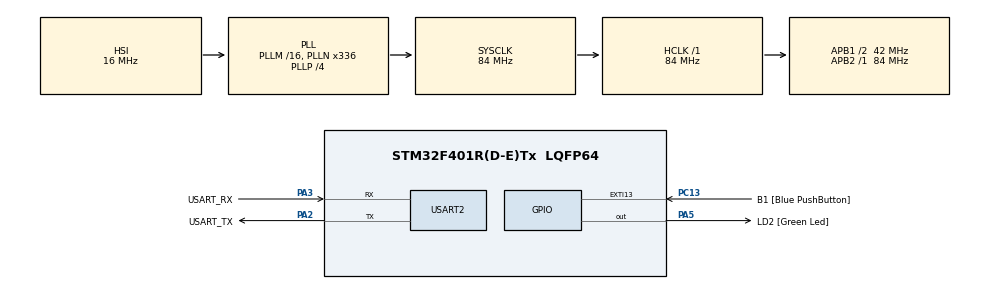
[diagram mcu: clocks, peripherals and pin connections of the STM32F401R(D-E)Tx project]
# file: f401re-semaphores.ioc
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FREERTOS.Tasks01=defaultTask,24,128,task_main,As weak,NULL,Dynamic,NULL,NULL
FREERTOS.configUSE_NEWLIB_REENTRANT=1
Mcu.Family=STM32F4
Mcu.Name=STM32F401R(D-E)Tx
Mcu.Package=LQFP64
NVIC.PriorityGroup=NVIC_PRIORITYGROUP_4
NVIC.TIM1_UP_TIM10_IRQn=true\:15\:0\:false\:false\:true\:false\:false\:true\:true
NVIC.TimeBase=TIM1_UP_TIM10_IRQn
NVIC.TimeBaseIP=TIM10
PA13.GPIO_Label=TMS
PA13.Mode=Trace_Asynchronous_SW
PA13.Signal=SYS_JTMS-SWDIO
PA14.GPIO_Label=TCK
PA14.Mode=Trace_Asynchronous_SW
PA14.Signal=SYS_JTCK-SWCLK
PA2.GPIO_Label=USART_TX
PA2.GPIO_Mode=GPIO_MODE_AF_PP
PA2.GPIO_PuPd=GPIO_NOPULL
PA2.GPIO_Speed=GPIO_SPEED_FREQ_LOW
PA2.Mode=Asynchronous
PA2.Signal=USART2_TX
PA3.GPIO_Label=USART_RX
PA3.GPIO_Mode=GPIO_MODE_AF_PP
PA3.GPIO_PuPd=GPIO_NOPULL
PA3.GPIO_Speed=GPIO_SPEED_FREQ_LOW
PA3.Mode=Asynchronous
PA3.Signal=USART2_RX
PA5.GPIO_Label=LD2 [Green Led]
PA5.GPIO_Mode=GPIO_MODE_OUTPUT_PP
PA5.GPIO_PuPd=GPIO_NOPULL
PA5.GPIO_Speed=GPIO_SPEED_FREQ_LOW
PA5.Signal=GPIO_Output
PB3.GPIO_Label=SWO
PB3.Mode=Trace_Asynchronous_SW
PB3.Signal=SYS_JTDO-SWO
PC13-ANTI_TAMP.GPIO_Label=B1 [Blue PushButton]
PC13-ANTI_TAMP.GPIO_ModeDefaultEXTI=GPIO_MODE_IT_FALLING
PC13-ANTI_TAMP.GPIO_PuPd=GPIO_NOPULL
PC13-ANTI_TAMP.Signal=GPXTI13
PC14-OSC32_IN.Mode=LSE-External-Oscillator
PC14-OSC32_IN.Signal=RCC_OSC32_IN
PC15-OSC32_OUT.Mode=LSE-External-Oscillator
PC15-OSC32_OUT.Signal=RCC_OSC32_OUT
PH0\ -\ OSC_IN.Mode=HSE-External-Clock-Source
PH0\ -\ OSC_IN.Signal=RCC_OSC_IN
PH1\ -\ OSC_OUT.Mode=HSE-External-Clock-Source
PH1\ -\ OSC_OUT.Signal=RCC_OSC_OUT
ProjectManager.HeapSize=0x200
ProjectManager.StackSize=0x400
ProjectManager.TargetToolchain=STM32CubeIDE
RCC.48MHZClocksFreq_Value=48000000
RCC.AHBFreq_Value=84000000
RCC.APB1CLKDivider=RCC_HCLK_DIV2
RCC.APB1Freq_Value=42000000
RCC.APB1TimFreq_Value=84000000
RCC.APB2Freq_Value=84000000
RCC.APB2TimFreq_Value=84000000
RCC.CortexFreq_Value=84000000
RCC.HCLKFreq_Value=84000000
RCC.HSE_VALUE=8000000
RCC.HSI_VALUE=16000000
RCC.PLLN=336
RCC.PLLP=RCC_PLLP_DIV4
RCC.PLLQ=7
RCC.SYSCLKFreq_VALUE=84000000
RCC.SYSCLKSource=RCC_SYSCLKSOURCE_PLLCLK
RCC.VCOOutputFreq_Value=336000000
USART2.VirtualMode=VM_ASYNC
VP_FREERTOS_VS_CMSIS_V2.Mode=CMSIS_V2
VP_SYS_VS_tim10.Mode=TIM10
board=NUCLEO-F401RE

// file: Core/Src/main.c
/* USER CODE BEGIN Header */
/**
  ******************************************************************************
  * @file           : main.c
  * @brief          : Main program body
  ******************************************************************************
  * @attention
  *
  * Copyright (c) 2025 STMicroelectronics.
  * All rights reserved.
  *
  * This software is licensed under terms that can be found in the LICENSE file
  * in the root directory of this software component.
  * If no LICENSE file comes with this software, it is provided AS-IS.
  *
  ******************************************************************************
  */
/* USER CODE END Header */
#include "main.h"
#include "cmsis_os.h"

/* USER CODE BEGIN Includes */
#include "stdio.h"
#include "string.h"
#include "freertos_defines.h"
/* USER CODE END Includes */

UART_HandleTypeDef huart2;

/* Definitions for defaultTask */
osThreadId_t defaultTaskHandle;
const osThreadAttr_t defaultTask_attributes = {
  .name = "defaultTask",
  .stack_size = 128 * 4,
  .priority = (osPriority_t) osPriorityNormal,
};
/* USER CODE BEGIN PV */

TaskHandle_t handle_task_main;
TaskHandle_t handle_task_green;
TaskHandle_t handle_task_blue;
TaskHandle_t handle_task_red;

SemaphoreHandle_t handle_semap_sem1;
SemaphoreHandle_t handle_semap_sem2;

/* USER CODE END PV */

void SystemClock_Config(void);
static void MX_GPIO_Init(void);
static void MX_USART2_UART_Init(void);
void task_main(void *argument);

int main(void)
{

  /* USER CODE BEGIN 1 */
  BaseType_t status;
  /* USER CODE END 1 */

  /* MCU Configuration--------------------------------------------------------*/

  /* Reset of all peripherals, Initializes the Flash interface and the Systick. */
  HAL_Init();

  /* Configure the system clock */
  SystemClock_Config();

  /* Initialize all configured peripherals */
  MX_GPIO_Init();
  MX_USART2_UART_Init();

  /* Init scheduler */
  osKernelInitialize();

  /* USER CODE BEGIN RTOS_SEMAPHORES */
  /* add semaphores, ... */
  handle_semap_sem1 = NULL;
  handle_semap_sem1 = xSemaphoreCreateBinary();
  xSemaphoreGive(handle_semap_sem1);
  //assert_param(handle_semap_sem1 != NULL);
  handle_semap_sem2 = NULL;
  handle_semap_sem2 = xSemaphoreCreateBinary();

  /* USER CODE END RTOS_SEMAPHORES */

  /* Create the thread(s) */
  /* creation of defaultTask */
  //defaultTaskHandle = osThreadNew(task_main, NULL, &defaultTask_attributes);

  /* USER CODE BEGIN RTOS_THREADS */
  /* add threads, ... */

  status = xTaskCreate(task_main, "Main task", 64, NULL, osPriorityNormal, &handle_task_main);
  //assert_param(status == pdPASS);

#ifdef HIGH_PRIORITY_EXAMPLE
  status = xTaskCreate(task_green, "Blinking green led task", 128, NULL, osPriorityHigh, &handle_task_green);

  //assert_param(status == pdPASS);
#else
  status = xTaskCreate(task_green, "Blinking green led task", 128, NULL, osPriorityNormal, &handle_task_green);
#endif

#ifdef HIGH_PRIORITY_EXAMPLE
  status = xTaskCreate(task_blue, "Blinking blue led task", 128, NULL, osPriorityNormal4, &handle_task_blue);
#else
  status = xTaskCreate(task_blue, "Blinking blue led task", 128, NULL, osPriorityNormal, &handle_task_blue);
#endif

#ifdef HIGH_PRIORITY_EXAMPLE
  status = xTaskCreate(task_red, "Blinking red led task", 64, NULL, osPriorityNormal, &handle_task_red);
#else
  status = xTaskCreate(task_red, "Blinking red led task", 64, NULL, osPriorityNormal, &handle_task_red);
#endif

  //assert_param(status == pdPASS);
  /* USER CODE END RTOS_THREADS */

  /* Start scheduler */
  osKernelStart();

  /* We should never get here as control is now taken by the scheduler */

  /* Infinite loop */
  while (1)
  {

  }
}

void SystemClock_Config(void)
{
  RCC_OscInitTypeDef RCC_OscInitStruct = {0};
  RCC_ClkInitTypeDef RCC_ClkInitStruct = {0};

  /** Configure the main internal regulator output voltage
  */
  __HAL_RCC_PWR_CLK_ENABLE();
  __HAL_PWR_VOLTAGESCALING_CONFIG(PWR_REGULATOR_VOLTAGE_SCALE2);

  /** Initializes the RCC Oscillators according to the specified parameters
  * in the RCC_OscInitTypeDef structure.
  */
  RCC_OscInitStruct.OscillatorType = RCC_OSCILLATORTYPE_HSI;
  RCC_OscInitStruct.HSIState = RCC_HSI_ON;
  RCC_OscInitStruct.HSICalibrationValue = RCC_HSICALIBRATION_DEFAULT;
  RCC_OscInitStruct.PLL.PLLState = RCC_PLL_ON;
  RCC_OscInitStruct.PLL.PLLSource = RCC_PLLSOURCE_HSI;
  RCC_OscInitStruct.PLL.PLLM = 16;
  RCC_OscInitStruct.PLL.PLLN = 336;
  RCC_OscInitStruct.PLL.PLLP = RCC_PLLP_DIV4;
  RCC_OscInitStruct.PLL.PLLQ = 7;
  if (HAL_RCC_OscConfig(&RCC_OscInitStruct) != HAL_OK)
  {
    Error_Handler();
  }

  /** Initializes the CPU, AHB and APB buses clocks
  */
  RCC_ClkInitStruct.ClockType = RCC_CLOCKTYPE_HCLK|RCC_CLOCKTYPE_SYSCLK
                              |RCC_CLOCKTYPE_PCLK1|RCC_CLOCKTYPE_PCLK2;
  RCC_ClkInitStruct.SYSCLKSource = RCC_SYSCLKSOURCE_PLLCLK;
  RCC_ClkInitStruct.AHBCLKDivider = RCC_SYSCLK_DIV1;
  RCC_ClkInitStruct.APB1CLKDivider = RCC_HCLK_DIV2;
  RCC_ClkInitStruct.APB2CLKDivider = RCC_HCLK_DIV1;

  if (HAL_RCC_ClockConfig(&RCC_ClkInitStruct, FLASH_LATENCY_2) != HAL_OK)
  {
    Error_Handler();
  }
}

static void MX_USART2_UART_Init(void)
{

  huart2.Instance = USART2;
  huart2.Init.BaudRate = 115200;
  huart2.Init.WordLength = UART_WORDLENGTH_8B;
  huart2.Init.StopBits = UART_STOPBITS_1;
  huart2.Init.Parity = UART_PARITY_NONE;
  huart2.Init.Mode = UART_MODE_TX_RX;
  huart2.Init.HwFlowCtl = UART_HWCONTROL_NONE;
  huart2.Init.OverSampling = UART_OVERSAMPLING_16;
  if (HAL_UART_Init(&huart2) != HAL_OK)
  {
    Error_Handler();
  }

}

static void MX_GPIO_Init(void)
{
  GPIO_InitTypeDef GPIO_InitStruct = {0};

  /* GPIO Ports Clock Enable */
  __HAL_RCC_GPIOC_CLK_ENABLE();
  __HAL_RCC_GPIOH_CLK_ENABLE();
  __HAL_RCC_GPIOA_CLK_ENABLE();
  __HAL_RCC_GPIOB_CLK_ENABLE();

  /*Configure GPIO pin Output Level */
  HAL_GPIO_WritePin(GPIOA, LED_GREEN_Pin|LED_BLUE_Pin|LED_RED_Pin, GPIO_PIN_RESET);

  /*Configure GPIO pin : B1_Pin */
  GPIO_InitStruct.Pin = B1_Pin;
  GPIO_InitStruct.Mode = GPIO_MODE_IT_FALLING;
  GPIO_InitStruct.Pull = GPIO_NOPULL;
  HAL_GPIO_Init(B1_GPIO_Port, &GPIO_InitStruct);

  /*Configure GPIO pins : LED_GREEN_Pin LED_BLUE_Pin LED_RED_Pin */
  GPIO_InitStruct.Pin = LED_GREEN_Pin|LED_BLUE_Pin|LED_RED_Pin;
  GPIO_InitStruct.Mode = GPIO_MODE_OUTPUT_PP;
  GPIO_InitStruct.Pull = GPIO_NOPULL;
  GPIO_InitStruct.Speed = GPIO_SPEED_FREQ_LOW;
  HAL_GPIO_Init(GPIOA, &GPIO_InitStruct);

}

__weak void task_main(void *argument)
{
}

void HAL_TIM_PeriodElapsedCallback(TIM_HandleTypeDef *htim)
{
  if (htim->Instance == TIM10) {
    HAL_IncTick();
  }
}

void Error_Handler(void)
{
  __disable_irq();
  while (1)
  {
  }
}

#ifdef  USE_FULL_ASSERT
/**
  * @brief  Reports the name of the source file and the source line number
  *         where the assert_param error has occurred.
  * @param  file: pointer to the source file name
  * @param  line: assert_param error line source number
  * @retval None
  */
void assert_failed(uint8_t *file, uint32_t line)
{
  /* USER CODE BEGIN 6 */
  /* User can add his own implementation to report the file name and line number,
     ex: printf("Wrong parameters value: file %s on line %d\r\n", file, line) */

	// Guardar error en una variable global o log (opcional)
	static uint32_t last_assert_line = 0;
	last_assert_line = line;
    printf("⚠️  Assert Fallido: Archivo %s, Línea %lu\n", file, line);

    // Enviar el mensaje por UART (opcional, si tienes una interfaz serial)
    char msg[100];
    snprintf(msg, sizeof(msg), "ASSERT FAILED: %s, LINE: %lu\n", file, line);
    HAL_UART_Transmit(&huart2, (uint8_t *)msg, strlen(msg), HAL_MAX_DELAY);

  /* USER CODE END 6 */
}
#endif /* USE_FULL_ASSERT */

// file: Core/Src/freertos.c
/* USER CODE BEGIN Header */
/**
  ******************************************************************************
  * File Name          : freertos.c
  * Description        : Code for freertos applications
  ******************************************************************************
  * @attention
  *
  * Copyright (c) 2025 STMicroelectronics.
  * All rights reserved.
  *
  * This software is licensed under terms that can be found in the LICENSE file
  * in the root directory of this software component.
  * If no LICENSE file comes with this software, it is provided AS-IS.
  *
  ******************************************************************************
  */
/* USER CODE END Header */

#include "FreeRTOS.h"
#include "task.h"
#include "main.h"

/* USER CODE BEGIN Includes */
#include "freertos_defines.h"
#include "stdlib.h"
/* USER CODE END Includes */

/* USER CODE BEGIN PD */
//#define PRUEBA_YIELD
//#define PRUEBA_SEMAP_2
//#define PRUEBA_POLLING
//#define PRUEBA_TIME_BOUND
/* USER CODE END PD */

/* USER CODE BEGIN Variables */
volatile uint32_t flag = 0;
/* USER CODE END Variables */

/* USER CODE BEGIN FunctionPrototypes */
static void lookBusy( uint32_t numIterations );
void Blinking_led(GPIO_TypeDef *gpio, uint8_t pin);
/* USER CODE END FunctionPrototypes */

/* USER CODE BEGIN Application */

void task_main(void *params)
{
	for(;;)
	{
		vTaskDelete(handle_task_main);
	}
}

void task_green(void *params)
{
	uint8_t cont = 0;

	for(;;)
	{
#ifdef PRUEBA_SEMAP_2
		/*Código con 2 semáforos*/
		if(xSemaphoreTake(handle_semap_sem1, portMAX_DELAY) == pdPASS)
		{
			for(cont = 0; cont < 5; cont++)
			{
				HAL_GPIO_WritePin(LED_GREEN_GPIO_Port, LED_GREEN_Pin, GPIO_PIN_SET);
				osDelay(150);
				HAL_GPIO_WritePin(LED_GREEN_GPIO_Port, LED_GREEN_Pin, GPIO_PIN_RESET);
				osDelay(150);
			}
			xSemaphoreGive(handle_semap_sem2);
		}
#endif

#ifdef PRUEBA_YIELD
		/*Código con taskYIELD*/
		if(xSemaphoreTake(handle_semap_sem1, portMAX_DELAY) == pdPASS)
		{
			for(cont = 0; cont < 5; cont++)
			{
				HAL_GPIO_WritePin(LED_GREEN_GPIO_Port, LED_GREEN_Pin, GPIO_PIN_SET);
				osDelay(150);
				HAL_GPIO_WritePin(LED_GREEN_GPIO_Port, LED_GREEN_Pin, GPIO_PIN_RESET);
				osDelay(150);
			}
			xSemaphoreGive(handle_semap_sem1);
			taskYIELD();
		}
#endif

#ifdef PRUEBA_POLLING

		if(++cont>5)
		{
			cont = 0;
			flag = 1;
		}
		HAL_GPIO_WritePin(LED_GREEN_GPIO_Port, LED_GREEN_Pin, GPIO_PIN_SET);
		osDelay(150);
		HAL_GPIO_WritePin(LED_GREEN_GPIO_Port, LED_GREEN_Pin, GPIO_PIN_RESET);
		osDelay(150);

#endif

#ifdef PRUEBA_TIME_BOUND
		uint8_t numLoops = (rand() % (7 + 1))+3;
		/*Blinking at 5Hz 50%*/
		if(++cont >= numLoops)
		{
			cont=0;
			xSemaphoreGive(handle_semap_sem1);
		}
		HAL_GPIO_WritePin(LED_GREEN_GPIO_Port, LED_GREEN_Pin, GPIO_PIN_SET);
		osDelay(100);
		HAL_GPIO_WritePin(LED_GREEN_GPIO_Port, LED_GREEN_Pin, GPIO_PIN_RESET);
		osDelay(100);
		/**/

#endif
#ifdef HIGH_PRIORITY_EXAMPLE
		if(xSemaphoreTake(handle_semap_sem1, pdMS_TO_TICKS(200))== pdPASS)
		{
			HAL_GPIO_WritePin(LED_RED_GPIO_Port, LED_RED_Pin, GPIO_PIN_RESET);
			Blinking_led(LED_GREEN_GPIO_Port, LED_GREEN_Pin);
			xSemaphoreGive(handle_semap_sem1);
		}
		else
		{
			HAL_GPIO_WritePin(LED_RED_GPIO_Port, LED_RED_Pin, GPIO_PIN_SET);
		}

		osDelay((rand()%(30-5+1))+5);

#endif
	}
}

void task_blue(void *params)
{
	uint32_t cont = 0;
	for(;;)
	{
#ifdef PRUEBA_SEMAP_2
		/*Código con 2 semáforos*/
		if(xSemaphoreTake(handle_semap_sem2, portMAX_DELAY) == pdPASS)
		{
			for(cont = 1; cont<=3; cont++)
			{
				HAL_GPIO_WritePin(LED_BLUE_GPIO_Port, LED_BLUE_Pin, GPIO_PIN_SET);
				osDelay(25);
				HAL_GPIO_WritePin(LED_BLUE_GPIO_Port, LED_BLUE_Pin, GPIO_PIN_RESET);
				osDelay(25);
			}
			xSemaphoreGive(handle_semap_sem1);
		}
#endif

#ifdef PRUEBA_YIELD
		/*Código con taskYIELD*/

        if(xSemaphoreTake(handle_semap_sem1, portMAX_DELAY) == pdPASS)
        {
            for(cont = 0; cont < 3; cont++)
            {
                HAL_GPIO_WritePin(LED_BLUE_GPIO_Port, LED_BLUE_Pin, GPIO_PIN_SET);
                osDelay(25);
                HAL_GPIO_WritePin(LED_BLUE_GPIO_Port, LED_BLUE_Pin, GPIO_PIN_RESET);
                osDelay(25);
            }
            xSemaphoreGive(handle_semap_sem1);
            taskYIELD();
        }
#endif

#ifdef PRUEBA_POLLING
        /*Código con polling*/
        if(flag!=0)
        {
        	for(cont = 1; cont <= 3; cont++)
        	{
                HAL_GPIO_WritePin(LED_BLUE_GPIO_Port, LED_BLUE_Pin, GPIO_PIN_SET);
                osDelay(25);
                HAL_GPIO_WritePin(LED_BLUE_GPIO_Port, LED_BLUE_Pin, GPIO_PIN_RESET);
                osDelay(25);
        	}
        	flag = 0;
        }
#endif

#ifdef PRUEBA_TIME_BOUND
        if(xSemaphoreTake(handle_semap_sem1, pdMS_TO_TICKS(500))==pdPASS)
		{
        	HAL_GPIO_WritePin(LED_RED_GPIO_Port, LED_RED_Pin, GPIO_PIN_RESET);
        	for(uint8_t i=1; i<=3; i++)
        	{
        		HAL_GPIO_WritePin(LED_BLUE_GPIO_Port, LED_BLUE_Pin, GPIO_PIN_SET);
				osDelay(50);
				HAL_GPIO_WritePin(LED_BLUE_GPIO_Port, LED_BLUE_Pin, GPIO_PIN_RESET);
				osDelay(50);
        	}
		}
        else
        {
        	HAL_GPIO_WritePin(LED_RED_GPIO_Port, LED_RED_Pin, GPIO_PIN_SET);
        }
#endif

#ifdef HIGH_PRIORITY_EXAMPLE

		osDelay(((rand()%(25-10+1))+10));
		cont = (rand()%(750000-250000+1))+250000;
		lookBusy(cont);

#endif
	}
}

void task_red(void *params)
{
	uint8_t cont = 0;
	for(;;)
	{

#ifdef PRUEBA_TIME_BOUND
		vTaskDelete(handle_task_red);
#endif

#ifdef HIGH_PRIORITY_EXAMPLE
	if(xSemaphoreTake(handle_semap_sem1, pdMS_TO_TICKS(200))==pdPASS)
	{
		HAL_GPIO_WritePin(LED_RED_GPIO_Port, LED_RED_Pin, GPIO_PIN_RESET);
		Blinking_led(LED_BLUE_GPIO_Port, LED_BLUE_Pin);
		xSemaphoreGive(handle_semap_sem1);
	}
	else
	{
		HAL_GPIO_WritePin(LED_RED_GPIO_Port, LED_RED_Pin, GPIO_PIN_SET);
	}
#endif

	}
}

void Blinking_led(GPIO_TypeDef *gpio, uint8_t pin)
{
	for(uint8_t i=1; i<=2; i++)
	{
		HAL_GPIO_WritePin(gpio, pin, GPIO_PIN_SET);
		osDelay(43);
		HAL_GPIO_WritePin(gpio, pin, GPIO_PIN_RESET);
		osDelay(43);
	}
}

static void lookBusy( uint32_t numIterations )
{
	__attribute__((unused))volatile uint32_t dontCare = 0;
	for(int i = 0; i < numIterations; i++)
	{
		dontCare = i % 4;
	}
}

/* USER CODE END Application */
